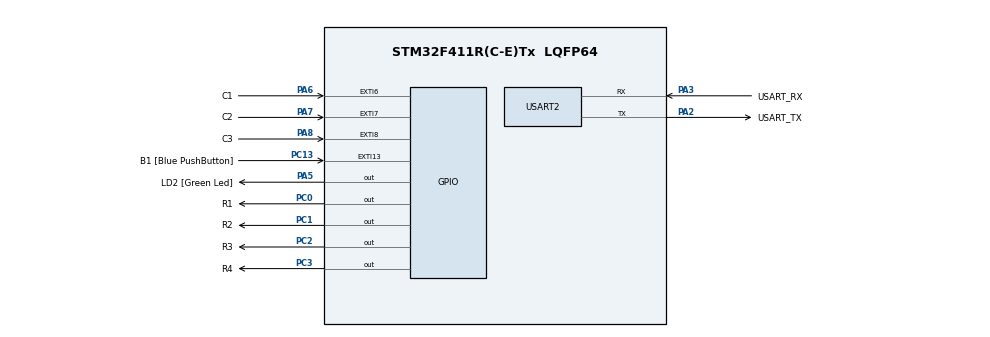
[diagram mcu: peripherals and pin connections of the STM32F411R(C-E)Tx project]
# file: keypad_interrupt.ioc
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Mcu.Family=STM32F4
Mcu.Name=STM32F411R(C-E)Tx
Mcu.Package=LQFP64
NVIC.EXTI9_5_IRQn=true\:0\:0\:false\:false\:true\:true\:true\:true
NVIC.PriorityGroup=NVIC_PRIORITYGROUP_0
PA13.GPIO_Label=TMS
PA13.Mode=Serial_Wire
PA13.Signal=SYS_JTMS-SWDIO
PA14.GPIO_Label=TCK
PA14.Mode=Serial_Wire
PA14.Signal=SYS_JTCK-SWCLK
PA2.GPIO_Label=USART_TX
PA2.Mode=Asynchronous
PA2.Signal=USART2_TX
PA3.GPIO_Label=USART_RX
PA3.Mode=Asynchronous
PA3.Signal=USART2_RX
PA5.GPIO_Label=LD2 [Green Led]
PA5.Signal=GPIO_Output
PA6.GPIO_Label=C1
PA6.GPIO_PuPd=GPIO_PULLUP
PA6.Signal=GPXTI6
PA7.GPIO_Label=C2
PA7.GPIO_PuPd=GPIO_PULLUP
PA7.Signal=GPXTI7
PA8.GPIO_Label=C3
PA8.GPIO_PuPd=GPIO_PULLUP
PA8.Signal=GPXTI8
PB3.GPIO_Label=SWO
PB3.Signal=SYS_JTDO-SWO
PC0.GPIO_Label=R1
PC0.Signal=GPIO_Output
PC1.GPIO_Label=R2
PC1.Signal=GPIO_Output
PC13-ANTI_TAMP.GPIO_Label=B1 [Blue PushButton]
PC13-ANTI_TAMP.GPIO_ModeDefaultEXTI=GPIO_MODE_IT_FALLING
PC13-ANTI_TAMP.Signal=GPXTI13
PC14-OSC32_IN.Mode=LSE-External-Oscillator
PC14-OSC32_IN.Signal=RCC_OSC32_IN
PC15-OSC32_OUT.Mode=LSE-External-Oscillator
PC15-OSC32_OUT.Signal=RCC_OSC32_OUT
PC2.GPIO_Label=R3
PC2.Signal=GPIO_Output
PC3.GPIO_Label=R4
PC3.Signal=GPIO_Output
PH0\ -\ OSC_IN.Mode=HSE-External-Clock-Source
PH0\ -\ OSC_IN.Signal=RCC_OSC_IN
PH1\ -\ OSC_OUT.Mode=HSE-External-Clock-Source
PH1\ -\ OSC_OUT.Signal=RCC_OSC_OUT
ProjectManager.HeapSize=0x200
ProjectManager.StackSize=0x400
ProjectManager.TargetToolchain=STM32CubeIDE
RCC.48MHZClocksFreq_Value=84000000
RCC.AHBFreq_Value=84000000
RCC.APB1CLKDivider=RCC_HCLK_DIV2
RCC.APB1Freq_Value=42000000
RCC.APB1TimFreq_Value=84000000
RCC.APB2Freq_Value=84000000
RCC.APB2TimFreq_Value=84000000
RCC.CortexFreq_Value=84000000
RCC.FLatency-AdvancedSettings=FLASH_LATENCY_2
RCC.HCLKFreq_Value=84000000
RCC.HSE_VALUE=8000000
RCC.HSI_VALUE=16000000
RCC.PLLN=336
RCC.PLLP=RCC_PLLP_DIV4
RCC.SYSCLKFreq_VALUE=84000000
RCC.SYSCLKSource=RCC_SYSCLKSOURCE_PLLCLK
RCC.VCOOutputFreq_Value=336000000
USART2.VirtualMode=VM_ASYNC
board=NUCLEO-F411RE

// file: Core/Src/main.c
/* USER CODE BEGIN Header */
/**
  ******************************************************************************
  * @file           : main.c
  * @brief          : Main program body
  ******************************************************************************
  * @attention
  *
  * Copyright (c) 2024 STMicroelectronics.
  * All rights reserved.
  *
  * This software is licensed under terms that can be found in the LICENSE file
  * in the root directory of this software component.
  * If no LICENSE file comes with this software, it is provided AS-IS.
  *
  ******************************************************************************
  */
/* USER CODE END Header */
#include "main.h"
#include "stdio.h"

#define DEBOUNCE_DELAY 50  // 50 milliseconds debounce delay

UART_HandleTypeDef huart2;

/* USER CODE BEGIN PV */
char keypad[4][3] = {
    {'1', '2', '3'},
    {'4', '5', '6'},
    {'7', '8', '9'},
    {'*', '0', '#'}
};

char pressed_key = 0;
volatile uint32_t last_keypress_time = 0;
/* USER CODE END PV */

void SystemClock_Config(void);
static void MX_GPIO_Init(void);
static void MX_USART2_UART_Init(void);

/* USER CODE BEGIN 0 */
int _write(int file, char *ptr, int len)
{
  (void)file;
  int DataIdx;

  for (DataIdx = 0; DataIdx < len; DataIdx++)
  {
    ITM_SendChar(*ptr++);
  }
  return len;
}

void delay(uint32_t ms)
{
    HAL_Delay(ms);
}

void scan_keypad(void)
{
    uint32_t current_time = HAL_GetTick();
    if (current_time - last_keypress_time < DEBOUNCE_DELAY)
    {
        return;  // Ignore this key press due to debounce
    }
    last_keypress_time = current_time;

    HAL_GPIO_WritePin(GPIOC, R1_Pin | R2_Pin | R3_Pin | R4_Pin, GPIO_PIN_SET);

    for (int row = 0; row < 4; row++)
    {
        HAL_GPIO_WritePin(GPIOC, (R1_Pin << row), GPIO_PIN_RESET);

        for (int col = 0; col < 3; col++)
        {
            if (HAL_GPIO_ReadPin(GPIOA, (C1_Pin << col)) == GPIO_PIN_RESET)
            {
                pressed_key = keypad[row][col];
                printf("Pressed Key: %c\n", pressed_key);
                printf("Scanning Row: %d\n", row);
                printf("Checking Column: %d, Pin State: %d\n", col, HAL_GPIO_ReadPin(GPIOA, (C1_Pin << col)));

                HAL_GPIO_WritePin(GPIOC, (R1_Pin << row), GPIO_PIN_SET);
                return;
            }
        }
        HAL_GPIO_WritePin(GPIOC, (R1_Pin << row), GPIO_PIN_SET);
    }
}

void HAL_GPIO_EXTI_Callback(uint16_t GPIO_Pin)
{
    if (GPIO_Pin == C1_Pin || GPIO_Pin == C2_Pin || GPIO_Pin == C3_Pin)
    {
        scan_keypad();
    }
}
/* USER CODE END 0 */

int main(void)
{
  /* USER CODE BEGIN 1 */
  /* Initialize the HAL Library */
  HAL_Init();
  /* USER CODE END 1 */

  /* MCU Configuration--------------------------------------------------------*/

  /* Reset of all peripherals, Initializes the Flash interface and the Systick. */
  HAL_Init();

  /* Configure the system clock */
  SystemClock_Config();

  /* Initialize all configured peripherals */
  MX_GPIO_Init();
  MX_USART2_UART_Init();

  /* USER CODE BEGIN 2 */
  /* Main loop */
  while (1)
  {
    /* USER CODE END WHILE */
	  printf("keypad");
    /* USER CODE BEGIN 3 */
    // Main loop code goes here
  }
  /* USER CODE END 3 */
}

void SystemClock_Config(void)
{
  RCC_OscInitTypeDef RCC_OscInitStruct = {0};
  RCC_ClkInitTypeDef RCC_ClkInitStruct = {0};

  /** Configure the main internal regulator output voltage
  */
  __HAL_RCC_PWR_CLK_ENABLE();
  __HAL_PWR_VOLTAGESCALING_CONFIG(PWR_REGULATOR_VOLTAGE_SCALE3);

  /** Initializes the RCC Oscillators according to the specified parameters
  * in the RCC_OscInitTypeDef structure.
  */
  RCC_OscInitStruct.OscillatorType = RCC_OSCILLATORTYPE_HSI;
  RCC_OscInitStruct.HSIState = RCC_HSI_ON;
  RCC_OscInitStruct.HSICalibrationValue = RCC_HSICALIBRATION_DEFAULT;
  RCC_OscInitStruct.PLL.PLLState = RCC_PLL_ON;
  RCC_OscInitStruct.PLL.PLLSource = RCC_PLLSOURCE_HSI;
  RCC_OscInitStruct.PLL.PLLM = 8;
  RCC_OscInitStruct.PLL.PLLN = 84;
  RCC_OscInitStruct.PLL.PLLP = RCC_PLLP_DIV2;
  RCC_OscInitStruct.PLL.PLLQ = 2;
  RCC_OscInitStruct.PLL.PLLM = 2;
  if (HAL_RCC_OscConfig(&RCC_OscInitStruct) != HAL_OK)
  {
    Error_Handler();
  }

  /** Initializes the CPU, AHB and APB buses clocks
  */
  RCC_ClkInitStruct.ClockType = RCC_CLOCKTYPE_HCLK|RCC_CLOCKTYPE_SYSCLK
                              |RCC_CLOCKTYPE_PCLK1|RCC_CLOCKTYPE_PCLK2;
  RCC_ClkInitStruct.SYSCLKSource = RCC_SYSCLKSOURCE_PLLCLK;
  RCC_ClkInitStruct.AHBCLKDivider = RCC_SYSCLK_DIV1;
  RCC_ClkInitStruct.APB1CLKDivider = RCC_HCLK_DIV2;
  RCC_ClkInitStruct.APB2CLKDivider = RCC_HCLK_DIV2;

  if (HAL_RCC_ClockConfig(&RCC_ClkInitStruct, FLASH_LATENCY_2) != HAL_OK)
  {
    Error_Handler();
  }
}

static void MX_USART2_UART_Init(void)
{
  huart2.Instance = USART2;
  huart2.Init.BaudRate = 115200;
  huart2.Init.WordLength = UART_WORDLENGTH_8B;
  huart2.Init.StopBits = UART_STOPBITS_1;
  huart2.Init.Parity = UART_PARITY_NONE;
  huart2.Init.Mode = UART_MODE_TX_RX;
  huart2.Init.HwFlowCtl = UART_HWCONTROL_NONE;
  huart2.Init.OverSampling = UART_OVERSAMPLING_16;
  if (HAL_UART_Init(&huart2) != HAL_OK)
  {
    Error_Handler();
  }
}

static void MX_GPIO_Init(void)
{
  GPIO_InitTypeDef GPIO_InitStruct = {0};

  /* GPIO Ports Clock Enable */
  __HAL_RCC_GPIOC_CLK_ENABLE();
  __HAL_RCC_GPIOH_CLK_ENABLE();
  __HAL_RCC_GPIOA_CLK_ENABLE();
  __HAL_RCC_GPIOB_CLK_ENABLE();

  /*Configure GPIO pin Output Level */
  HAL_GPIO_WritePin(GPIOC, R1_Pin|R2_Pin|R3_Pin|R4_Pin, GPIO_PIN_RESET);

  /*Configure GPIO pin Output Level */
  HAL_GPIO_WritePin(LD2_GPIO_Port, LD2_Pin, GPIO_PIN_RESET);

  /*Configure GPIO pin : B1_Pin */
  GPIO_InitStruct.Pin = B1_Pin;
  GPIO_InitStruct.Mode = GPIO_MODE_IT_FALLING;
  GPIO_InitStruct.Pull = GPIO_NOPULL;
  HAL_GPIO_Init(B1_GPIO_Port, &GPIO_InitStruct);

  /*Configure GPIO pins : R1_Pin R2_Pin R3_Pin R4_Pin */
  GPIO_InitStruct.Pin = R1_Pin|R2_Pin|R3_Pin|R4_Pin;
  GPIO_InitStruct.Mode = GPIO_MODE_OUTPUT_PP;
  GPIO_InitStruct.Pull = GPIO_NOPULL;
  GPIO_InitStruct.Speed = GPIO_SPEED_FREQ_LOW;
  HAL_GPIO_Init(GPIOC, &GPIO_InitStruct);

  /*Configure GPIO pin : LD2_Pin */
  GPIO_InitStruct.Pin = LD2_Pin;
  GPIO_InitStruct.Mode = GPIO_MODE_OUTPUT_PP;
  GPIO_InitStruct.Pull = GPIO_NOPULL;
  GPIO_InitStruct.Speed = GPIO_SPEED_FREQ_LOW;
  HAL_GPIO_Init(LD2_GPIO_Port, &GPIO_InitStruct);

  /*Configure GPIO pins : C1_Pin C2_Pin C3_Pin */
  GPIO_InitStruct.Pin = C1_Pin|C2_Pin|C3_Pin;
  GPIO_InitStruct.Mode = GPIO_MODE_IT_FALLING;
  GPIO_InitStruct.Pull = GPIO_PULLUP;
  HAL_GPIO_Init(GPIOA, &GPIO_InitStruct);

  /* EXTI interrupt init*/
  HAL_NVIC_SetPriority(EXTI9_5_IRQn, 0, 0);
  HAL_NVIC_EnableIRQ(EXTI9_5_IRQn);
}

/* USER CODE BEGIN 4 */

void Error_Handler(void)
{
  __disable_irq();
  while (1)
  {
  }
}
